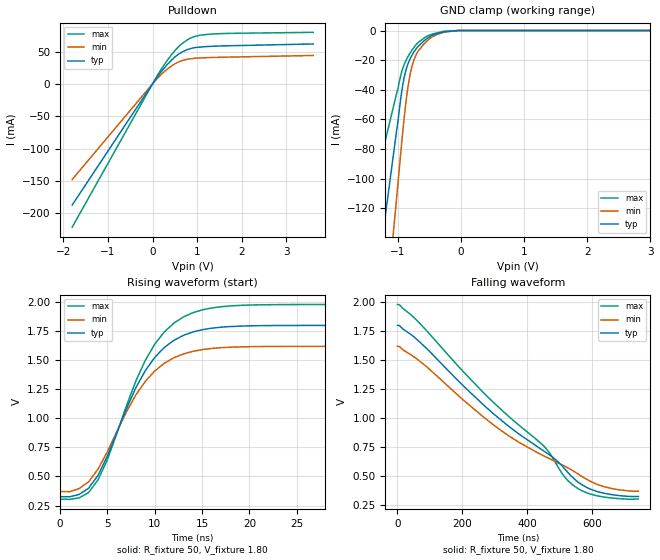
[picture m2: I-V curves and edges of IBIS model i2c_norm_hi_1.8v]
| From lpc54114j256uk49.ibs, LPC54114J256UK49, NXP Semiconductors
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[Model]   i2c_norm_hi_1.8v
Model_type I/O_open_drain
Vinl=4.000E-01
Vinh=1.500E+00
Vref=1.800E+00
Rref=1.000E+03
Cref=0.000E+00
Vmeas=9.000E-01
C_comp   9.060E-12   8.700E-12   9.420E-12
[Voltage Range]   1.800E+00   1.620E+00   1.980E+00
[POWER Clamp Reference]   1.800E+00   1.620E+00   1.980E+00
[GND Clamp Reference]   0.000E+00   0.000E+00   0.000E+00
[Pullup Reference]   1.800E+00   1.620E+00   1.980E+00
[Pulldown Reference]   0.000E+00   0.000E+00   0.000E+00
[Temperature Range]   25   105   -40
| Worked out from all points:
|   slope of the pulldown table from 0 to 0.27 V, typ, clamps not added: 10.8 ohm
|   GND clamp passes 1 mA (typ) near -0.28 V on its own axis
|   rising waveform, R_fixture 50, V_fixture 1.80: 20-80 % time 5.16ns typ, 5.19ns min, 5.09ns max; typ from 0.326 V to 1.8 V
|   falling waveform, R_fixture 50, V_fixture 1.80: 20-80 % time 373ns typ, 373ns min, 358ns max; typ from 1.8 V to 0.326 V
[GND Clamp]
-1.8V     -317.5mA   -470.6mA   -180.8mA
-1.02V    -67.02mA   -112.2mA   -42.21mA
-960mV    -47.03mA   -84.4mA    -30.98mA
-920mV    -35.66mA   -66.42mA   -25.01mA
-860mV    -24.73mA   -43.61mA   -19.06mA
-820mV    -20.23mA   -32.4mA    -16.03mA
-780mV    -16.82mA   -24.47mA   -13.4mA
-720mV    -12.79mA   -17.03mA   -9.921mA
-540mV    -5.346mA   -6.995mA   -3.83mA
-360mV    -1.801mA   -2.351mA   -1.381mA
-40mV     0A         0A         0A
3.6V      0A         0A         0A
[Pulldown]
-1.8V     -187.3mA   -147.9mA   -221.6mA
140mV     13.87mA    10.72mA    16.57mA
420mV     36.34mA    27.43mA    44.64mA
540mV     43.69mA    32.43mA    54.3mA
660mV     49.17mA    35.87mA    62.04mA
840mV     54.31mA    38.72mA    70.35mA
960mV     56.15mA    39.63mA    73.54mA
1.32V     58.1mA     40.79mA    76.98mA
3.6V      61.72mA    43.88mA    79.7mA
[Rising Waveform]
R_fixture = 50
V_fixture = 1.80
V_fixture_min = 1.62
V_fixture_max = 1.98
0s        325.7mV    370.6mV    303.7mV
2ns       345.1mV    395.4mV    315.5mV
4ns       509.7mV    562.9mV    470.2mV
5ns       676.8mV    715.1mV    646.1mV
7ns       1.083V     1.056V     1.107V
9ns       1.411V     1.319V     1.5V
11ns      1.61V      1.474V     1.744V
13ns      1.714V     1.554V     1.872V
19ns      1.794V     1.615V     1.972V
43ns      1.8V       1.62V      1.98V
[Falling Waveform]
R_fixture = 50
V_fixture = 1.80
V_fixture_min = 1.62
V_fixture_max = 1.98
0s        1.8V       1.62V      1.98V
68ns      1.66V      1.493V     1.82V
206ns     1.272V     1.151V     1.394V
325ns     972.9mV    884.7mV    1.063V
454ns     713.8mV    672.8mV    755.1mV
510ns     584.7mV    596.5mV    517.7mV
540ns     492.6mV    550.7mV    427.8mV
575ns     418mV      489.4mV    368.6mV
615ns     369.7mV    432.2mV    332.5mV
744ns     325.7mV    370.6mV    303.7mV
[Ramp]
dV/dt_r   8.8457E-01/5.1050E-09   7.4965E-01/5.1310E-09   1.0058E+00/5.0770E-09
dV/dt_f   8.8457E-01/3.7368E-07   7.4965E-01/3.7241E-07   1.0058E+00/3.5839E-07
R_load = 50
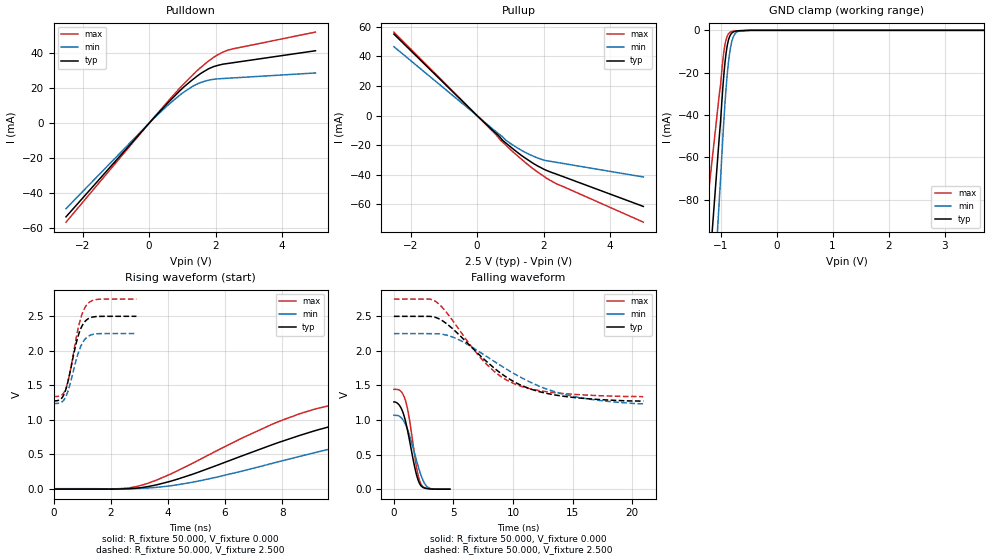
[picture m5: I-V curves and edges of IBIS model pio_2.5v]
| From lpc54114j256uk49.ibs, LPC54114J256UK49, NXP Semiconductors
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[Model]   pio_2.5v
Model_type I/O
Vinl=4.000E-01
Vinh=1.500E+00
Vref=0.000E+00
Rref=1.000E+06
Cref=2.000E-11
Vmeas=1.250E+00
C_comp   9.060E-12   8.700E-12   9.420E-12
[Voltage Range]   2.500E+00   2.250E+00   2.750E+00
[POWER Clamp Reference]   2.500E+00   2.250E+00   2.750E+00
[GND Clamp Reference]   0.000E+00   0.000E+00   0.000E+00
[Pullup Reference]   2.500E+00   2.250E+00   2.750E+00
[Pulldown Reference]   0.000E+00   0.000E+00   0.000E+00
[Temperature Range]   25   105   -40
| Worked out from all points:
|   slope of the pulldown table from 0 to 0.375 V, typ, clamps not added: 48.2 ohm
|   slope of the pullup table from 0 to 0.375 V, typ, clamps not added: 47.2 ohm
|   GND clamp passes 1 mA (typ) near -0.78 V on its own axis
|   rising waveform, R_fixture 50.000, V_fixture 0.000: 20-80 % time 5.59ns typ, 6.98ns min, 4.66ns max; typ from -0.006 V to 1.26 V
|   falling waveform, R_fixture 50.000, V_fixture 0.000: 20-80 % time 902ps typ, 1.09ns min, 781ps max; typ from 1.26 V to 0 V
|   rising waveform, R_fixture 50.000, V_fixture 2.500: 20-80 % time 408ps typ, 413ps min, 407ps max; typ from 1.27 V to 2.5 V
|   falling waveform, R_fixture 50.000, V_fixture 2.500: 20-80 % time 5.14ns typ, 6.37ns min, 4.26ns max; typ from 2.5 V to 1.27 V
[GND Clamp]
-2.5V     -572.1mA   -752.8mA   -387.4mA
-1.02V    -49.35mA   -78.96mA   -29.69mA
-1V       -43.14mA   -70.39mA   -25.78mA
-960mV    -27.26mA   -51.07mA   -14.22mA
-920mV    -14.96mA   -34.05mA   -6.512mA
-880mV    -7.1mA     -20.57mA   -2.66mA
-860mV    -4.685mA   -15.34mA   -1.691mA
-820mV    -1.992mA   -7.818mA   -747.3uA
-780mV    -901.4uA   -3.603mA   -417.6uA
-740mV    -479.8uA   -1.555mA   -285.4uA
-540mV    -71.71uA   -88.6uA    -61.47uA
5V        0A         0A         0A
[Power Clamp]
-2.5V     0A         0A         0A
0V        0A         0A         0A
2.5V      0A         0A         0A
5V        0A         0A         0A
[Pullup]
-2.5V     55.03mA    46.51mA    56.39mA
0V        0A         0A         0A
560mV     -11.71mA   -10.66mA   -12.69mA
760mV     -16.48mA   -14.18mA   -17.72mA
1V        -20.97mA   -18.73mA   -22.83mA
1.42V     -28.23mA   -24.51mA   -31.07mA
1.96V     -35.62mA   -29.68mA   -40.25mA
2.38V     -39.45mA   -31.53mA   -45.93mA
5V        -61.32mA   -41.44mA   -71.95mA
[Pulldown]
-2.5V     -53.75mA   -49.06mA   -56.82mA
0V        0A         0A         0A
360mV     7.48mA     6.68mA     7.998mA
980mV     19.59mA    16.96mA    21.32mA
1.32V     25.16mA    21.25mA    27.81mA
1.54V     28.36mA    23.25mA    31.74mA
1.94V     32.45mA    25.18mA    37.76mA
2.36V     34.22mA    25.76mA    41.85mA
5V        41.54mA    28.79mA    52.24mA
[Rising Waveform]
R_fixture = 50.000
V_fixture = 0.000
V_fixture_min = 0.000
V_fixture_max = 0.000
|  time   V(typ)   V(min)   V(max)
0s        -5.765mV   0V         -1.766mV
2.3ns     -4.275mV   -258.9uV   -144.2uV
3.15ns    20.28mV    7.404mV    58.7mV
5ns       229.5mV    105mV      397.3mV
7.9ns     674.2mV    393.7mV    977.9mV
9.15ns    841.3mV    523.9mV    1.155V
10.4ns    976.6mV    645.2mV    1.265V
12.45ns   1.114V     810.7mV    1.354V
15.5ns    1.201V     958.7mV    1.409V
22.85ns   1.256V     1.069V     1.441V
[Falling Waveform]
R_fixture = 50.000
V_fixture = 0.000
V_fixture_min = 0.000
V_fixture_max = 0.000
|  time   V(typ)   V(min)   V(max)
0s        1.262V     1.069V     1.444V
550ps     1.19V      1.044V     1.421V
1ns       962.4mV    927.7mV    1.265V
1.3ns     714.9mV    783mV      1.01V
1.85ns    241.1mV    444.6mV    369.8mV
2.1ns     102.3mV    293.7mV    153.1mV
2.3ns     44.37mV    189.4mV    64.17mV
2.6ns     14.55mV    76.54mV    21.16mV
2.95ns    4.239mV    17.38mV    8.081mV
4.7ns     0V         0V         0V
[Rising Waveform]
R_fixture = 50.000
V_fixture = 2.500
V_fixture_min = 2.250
V_fixture_max = 2.750
|  time   V(typ)   V(min)   V(max)
0s        1.274V     1.235V     1.337V
250ps     1.298V     1.248V     1.349V
350ps     1.353V     1.28V      1.385V
450ps     1.465V     1.352V     1.475V
600ps     1.734V     1.549V     1.738V
850ps     2.199V     1.947V     2.302V
1ns       2.363V     2.105V     2.534V
1.2ns     2.461V     2.206V     2.684V
1.55ns    2.498V     2.247V     2.745V
2.9ns     2.5V       2.25V      2.75V
[Falling Waveform]
R_fixture = 50.000
V_fixture = 2.500
V_fixture_min = 2.250
V_fixture_max = 2.750
|  time   V(typ)   V(min)   V(max)
0s        2.5V       2.25V      2.75V
2.95ns    2.499V     2.25V      2.749V
3.55ns    2.481V     2.248V     2.71V
5.25ns    2.27V      2.178V     2.363V
7.7ns     1.859V     1.929V     1.82V
8.95ns    1.68V      1.79V      1.634V
10.25ns   1.539V     1.655V     1.515V
12.25ns   1.409V     1.486V     1.425V
14.65ns   1.335V     1.357V     1.377V
20.95ns   1.274V     1.235V     1.337V
[Ramp]
dV/dt_r   7.5711E-01/5.5865E-09   6.3920E-01/6.9663E-09   8.6573E-01/4.6619E-09
dV/dt_f   7.3584E-01/5.1385E-09   6.0892E-01/6.3638E-09   8.4764E-01/4.2601E-09
R_load = 50
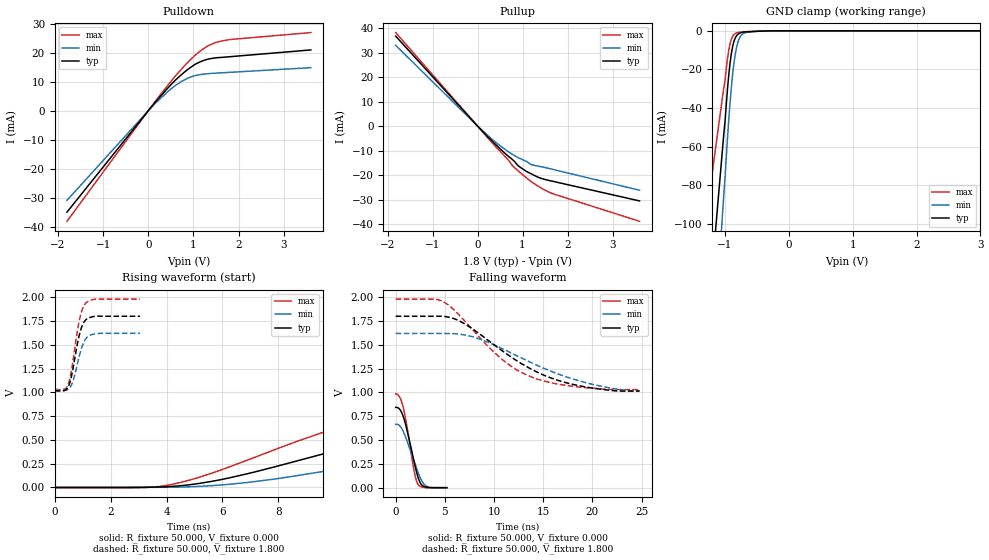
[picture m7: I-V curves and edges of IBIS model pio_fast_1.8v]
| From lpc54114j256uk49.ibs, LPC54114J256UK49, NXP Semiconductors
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[Model]   pio_fast_1.8v
Model_type I/O
Vinl=4.000E-01
Vinh=1.500E+00
Vref=0.000E+00
Rref=1.000E+06
Cref=2.000E-11
Vmeas=9.000E-01
C_comp   9.060E-12   8.700E-12   9.420E-12
[Voltage Range]   1.800E+00   1.620E+00   1.980E+00
[POWER Clamp Reference]   1.800E+00   1.620E+00   1.980E+00
[GND Clamp Reference]   0.000E+00   0.000E+00   0.000E+00
[Pullup Reference]   1.800E+00   1.620E+00   1.980E+00
[Pulldown Reference]   0.000E+00   0.000E+00   0.000E+00
[Temperature Range]   25   105   -40
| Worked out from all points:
|   slope of the pulldown table from 0 to 0.27 V, typ, clamps not added: 54.4 ohm
|   slope of the pullup table from 0 to 0.27 V, typ, clamps not added: 52.3 ohm
|   GND clamp passes 1 mA (typ) near -0.75 V on its own axis
|   rising waveform, R_fixture 50.000, V_fixture 0.000: 20-80 % time 7.6ns typ, 8.94ns min, 6.14ns max; typ from 0 V to 0.844 V
|   falling waveform, R_fixture 50.000, V_fixture 0.000: 20-80 % time 1.13ns typ, 1.38ns min, 947ps max; typ from 0.844 V to 0 V
|   rising waveform, R_fixture 50.000, V_fixture 1.800: 20-80 % time 315ps typ, 326ps min, 312ps max; typ from 1.01 V to 1.8 V
|   falling waveform, R_fixture 50.000, V_fixture 1.800: 20-80 % time 7.15ns typ, 8.09ns min, 5.95ns max; typ from 1.8 V to 1.01 V
[GND Clamp]
-1.8V     -355.1mA   -471.4mA   -219.5mA
-1.02V    -54.19mA   -85.87mA   -29.93mA
-1V       -47.41mA   -76.6mA    -26.06mA
-960mV    -30.06mA   -55.56mA   -14.3mA
-920mV    -16.65mA   -37.14mA   -6.668mA
-880mV    -8.151mA   -22.59mA   -2.912mA
-840mV    -3.76mA    -12.4mA    -1.435mA
-800mV    -1.864mA   -6.201mA   -885.5uA
-740mV    -860uA     -2.128mA   -623.1uA
-680mV    -560.3uA   -950.5uA   -447.4uA
-540mV    -310.6uA   -397.7uA   -251.2uA
3.6V      0A         0A         0A
[Power Clamp]
-1.8V     0A         0A         0A
0V        0A         0A         0A
1.8V      0A         0A         0A
3.6V      0A         0A         0A
[Pullup]
-1.82V    36.68mA    32.95mA    38.14mA
60mV      -1.186mA   -1.045mA   -1.256mA
520mV     -9.605mA   -8.289mA   -10.63mA
680mV     -12.23mA   -10.39mA   -13.75mA
780mV     -13.74mA   -11.58mA   -16.2mA
900mV     -16.13mA   -12.84mA   -18.25mA
1V        -17.45mA   -13.7mA    -19.78mA
1.2V      -19.53mA   -15.73mA   -22.73mA
1.42V     -21.36mA   -16.58mA   -25.34mA
1.62V     -22.32mA   -17.43mA   -27.21mA
3.6V      -30.52mA   -26.17mA   -38.83mA
[Pulldown]
-1.8V     -34.9mA    -30.86mA   -38.06mA
0V        0A         0A         0A
400mV     7.25mA     6.14mA     8.117mA
600mV     10.52mA    8.704mA    11.94mA
820mV     13.55mA    10.8mA     15.78mA
1.02V     15.83mA    12.03mA    18.86mA
1.16V     16.92mA    12.47mA    20.67mA
1.32V     17.75mA    12.77mA    22.31mA
1.48V     18.2mA     12.94mA    23.43mA
1.8V      18.6mA     13.23mA    24.51mA
3.6V      20.95mA    14.84mA    26.92mA
[Rising Waveform]
R_fixture = 50.000
V_fixture = 0.000
V_fixture_min = 0.000
V_fixture_max = 0.000
|  time   V(typ)   V(min)   V(max)
0s        0V         0V         -5.148mV
3.15ns    1.027mV    247.2uV    -3.175mV
4.25ns    11.17mV    1.845mV    34.99mV
6.25ns    100.2mV    32.48mV    215.6mV
10.3ns    404.9mV    202.3mV    644.2mV
11.85ns   514.5mV    282.1mV    763.1mV
13.5ns    612.4mV    363.7mV    849.4mV
16ns      718.3mV    470.3mV    919.6mV
18.35ns   777.4mV    548.6mV    952.7mV
25.05ns   844mV      665.8mV    979.7mV
[Falling Waveform]
R_fixture = 50.000
V_fixture = 0.000
V_fixture_min = 0.000
V_fixture_max = 0.000
|  time   V(typ)   V(min)   V(max)
0s        844mV      665.8mV    985.1mV
400ps     824.4mV    651.2mV    951.4mV
750ps     753.5mV    595mV      851.7mV
1.15ns    605mV      491.5mV    641.3mV
1.85ns    283.4mV    284.1mV    188.9mV
2.05ns    194mV      225.1mV    94.91mV
2.25ns    117.7mV    168.4mV    39.42mV
2.6ns     34.92mV    84.21mV    9.395mV
3.15ns    5.273mV    13.71mV    -762.4uV
5.2ns     0V         0V         0V
[Rising Waveform]
R_fixture = 50.000
V_fixture = 1.800
V_fixture_min = 1.620
V_fixture_max = 1.980
|  time   V(typ)   V(min)   V(max)
0s        1.014V     1.019V     1.03V
350ps     1.019V     1.02V      1.035V
500ps     1.069V     1.035V     1.099V
650ps     1.246V     1.116V     1.327V
800ps     1.495V     1.287V     1.629V
900ps     1.628V     1.408V     1.785V
1ns       1.714V     1.501V     1.884V
1.1ns     1.759V     1.559V     1.935V
1.55ns    1.801V     1.619V     1.98V
3.05ns    1.8V       1.62V      1.98V
[Falling Waveform]
R_fixture = 50.000
V_fixture = 1.800
V_fixture_min = 1.620
V_fixture_max = 1.980
|  time   V(typ)   V(min)   V(max)
0s        1.8V       1.62V      1.98V
4ns       1.8V       1.62V      1.98V
4.95ns    1.798V     1.619V     1.946V
7.05ns    1.718V     1.603V     1.747V
10.75ns   1.444V     1.464V     1.354V
12.2ns    1.341V     1.391V     1.244V
13.95ns   1.236V     1.305V     1.157V
18.75ns   1.069V     1.119V     1.056V
22.65ns   1.015V     1.032V     1.03V
24.8ns    1.014V     1.019V     1.03V
[Ramp]
dV/dt_r   5.0453E-01/7.5936E-09   4.0062E-01/8.9309E-09   5.9090E-01/6.1396E-09
dV/dt_f   4.7142E-01/7.1409E-09   3.6076E-01/8.0730E-09   5.6989E-01/5.9432E-09
R_load = 50
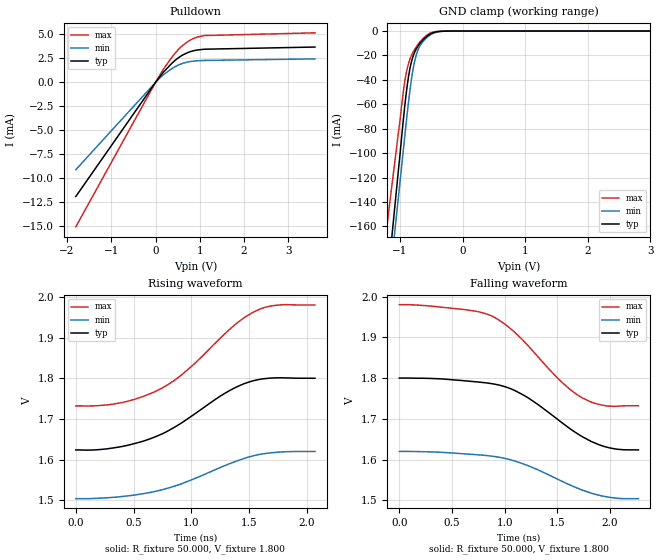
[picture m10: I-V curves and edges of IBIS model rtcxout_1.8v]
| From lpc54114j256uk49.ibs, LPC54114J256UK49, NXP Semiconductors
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[Model]   rtcxout_1.8v
Model_type Open_drain
Vref=1.800E+00
Rref=1.000E+03
Cref=0.000E+00
Vmeas=9.000E-01
C_comp   1.410E-12   1.370E-12   1.450E-12
[Voltage Range]   1.800E+00   1.620E+00   1.980E+00
[POWER Clamp Reference]   1.800E+00   1.620E+00   1.980E+00
[GND Clamp Reference]   0.000E+00   0.000E+00   0.000E+00
[Pullup Reference]   1.800E+00   1.620E+00   1.980E+00
[Pulldown Reference]   0.000E+00   0.000E+00   0.000E+00
[Temperature Range]   25   85   -40
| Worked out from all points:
|   slope of the pulldown table from 0 to 0.27 V, typ, clamps not added: 178 ohm
|   GND clamp passes 1 mA (typ) near -0.45 V on its own axis
|   rising waveform, R_fixture 50.000, V_fixture 1.800: 20-80 % time 589ps typ, 630ps min, 592ps max; typ from 1.62 V to 1.8 V
|   falling waveform, R_fixture 50.000, V_fixture 1.800: 20-80 % time 587ps typ, 625ps min, 569ps max; typ from 1.8 V to 1.62 V
[GND Clamp]
-1.8V     -518.4mA   -516.4mA   -407.5mA
-1.02V    -112.2mA   -134.3mA   -81.71mA
-920mV    -60.54mA   -85.34mA   -40.76mA
-860mV    -36.66mA   -57.26mA   -26.19mA
-820mV    -26.09mA   -41.17mA   -20.51mA
-780mV    -19.28mA   -28.6mA    -16.46mA
-720mV    -13.02mA   -16.74mA   -11.65mA
-660mV    -8.855mA   -10.54mA   -7.768mA
-540mV    -3.186mA   -4.102mA   -2.377mA
-420mV    -668.8uA   -1.063mA   -384.5uA
-260mV    -65.28uA   -110.4uA   -38.84uA
3.6V      0A         0A         0A
[Pulldown]
-1.8V     -11.91mA   -9.109mA   -15.07mA
20mV      128.4uA    97.53uA    163.8uA
180mV     1.074mA    798.3uA    1.39mA
380mV     2.043mA    1.474mA    2.69mA
620mV     2.877mA    2mA        3.885mA
860mV     3.308mA    2.223mA    4.589mA
1.1V      3.464mA    2.292mA    4.888mA
3.6V      3.69mA     2.455mA    5.173mA
[Rising Waveform]
R_fixture = 50.000
V_fixture = 1.800
V_fixture_min = 1.620
V_fixture_max = 1.980
|  time   V(typ)   V(min)   V(max)
0s        1.624V     1.504V     1.732V
320ps     1.629V     1.507V     1.736V
650ps     1.652V     1.52V      1.763V
790ps     1.669V     1.529V     1.783V
910ps     1.689V     1.54V      1.807V
1.29ns    1.763V     1.585V     1.909V
1.43ns    1.783V     1.6V       1.943V
1.53ns    1.793V     1.609V     1.961V
1.72ns    1.801V     1.617V     1.979V
2.07ns    1.8V       1.62V      1.98V
[Falling Waveform]
R_fixture = 50.000
V_fixture = 1.800
V_fixture_min = 1.620
V_fixture_max = 1.980
|  time   V(typ)   V(min)   V(max)
0s        1.8V       1.62V      1.98V
620ps     1.793V     1.614V     1.968V
860ps     1.787V     1.609V     1.954V
1ns       1.779V     1.603V     1.932V
1.17ns    1.759V     1.59V      1.894V
1.51ns    1.697V     1.551V     1.798V
1.72ns    1.659V     1.527V     1.754V
1.83ns    1.643V     1.517V     1.74V
1.98ns    1.63V      1.508V     1.731V
2.27ns    1.624V     1.504V     1.732V
[Ramp]
dV/dt_r   1.0573E-01/5.8620E-10   7.0000E-02/6.3080E-10   1.5069E-01/5.9160E-10
dV/dt_f   1.0573E-01/5.8625E-10   7.0000E-02/6.2422E-10   1.5069E-01/5.6734E-10
R_load = 50
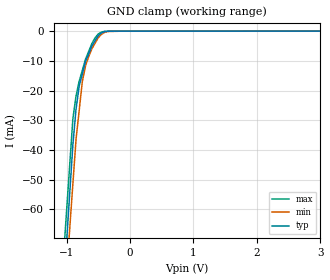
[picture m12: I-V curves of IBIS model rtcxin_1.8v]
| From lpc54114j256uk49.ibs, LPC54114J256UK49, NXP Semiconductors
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[Model] rtcxin_1.8v
Model_type Terminator
C_comp 1.70000pF 1.70000pF 1.70000pF
| variable typ   min   max
[Voltage Range] 1.80000V 1.62000V 1.98000V
[POWER Clamp Reference] 1.80000V 1.62000V 1.98000V
[GND Clamp Reference] 0.00000V 0.00000V 0.00000V
[Temperature Range]   25   85   -40
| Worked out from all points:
|   GND clamp passes 1 mA (typ) near -0.47 V on its own axis
[GND Clamp]
-1.8V     -335.4mA   -324mA     -312mA
-900mV    -38.3mA    -51.53mA   -29.53mA
-850mV    -26.25mA   -36.39mA   -21.8mA
-800mV    -18.48mA   -26.6mA    -16.83mA
-750mV    -14.33mA   -16.82mA   -13.12mA
-700mV    -10.18mA   -11.63mA   -9.41mA
-600mV    -5.005mA   -5.914mA   -4.175mA
-550mV    -3.256mA   -4.06mA    -2.226mA
-450mV    -591.4uA   -1.074mA   -284.5uA
-350mV    -34.67uA   -121.2uA   -44.77uA
-175mV    -6.5uA     -27.89uA   -8.594uA
3.6V      11.58uA    24.71uA    11.52uA
[POWER Clamp]
-1.8V     0A         0A         0A
3.6V      0A         0A         0A
